VERSION 5.7 ;
  NOWIREEXTENSIONATPIN ON ;
  DIVIDERCHAR "/" ;
  BUSBITCHARS "[]" ;
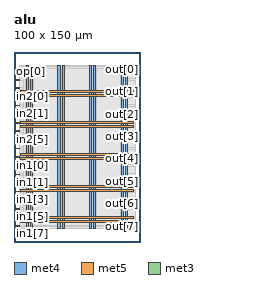
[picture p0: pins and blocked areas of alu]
MACRO alu
  CLASS BLOCK ;
  FOREIGN alu ;
  ORIGIN 0.000 0.000 ;
  SIZE 100.000 BY 150.000 ;
  PIN VGND
    DIRECTION INOUT ;
    USE GROUND ;
    PORT
      LAYER met4 ;
        RECT 13.020 10.640 14.620 138.960 ;
    END
    PORT
      LAYER met4 ;
        RECT 38.020 10.640 39.620 138.960 ;
    END
    PORT
      LAYER met4 ;
        RECT 63.020 10.640 64.620 138.960 ;
    END
    PORT
      LAYER met4 ;
        RECT 88.020 10.640 89.620 138.960 ;
    END
    PORT
      LAYER met5 ;
        RECT 5.280 18.380 94.540 19.980 ;
    END
    PORT
      LAYER met5 ;
        RECT 5.280 43.380 94.540 44.980 ;
    END
    PORT
      LAYER met5 ;
        RECT 5.280 68.380 94.540 69.980 ;
    END
    PORT
      LAYER met5 ;
        RECT 5.280 93.380 94.540 94.980 ;
    END
    PORT
      LAYER met5 ;
        RECT 5.280 118.380 94.540 119.980 ;
    END
  END VGND
  PIN VPWR
    DIRECTION INOUT ;
    USE POWER ;
    PORT
      LAYER met4 ;
        RECT 9.720 10.640 11.320 138.960 ;
    END
    PORT
      LAYER met4 ;
        RECT 34.720 10.640 36.320 138.960 ;
    END
    PORT
      LAYER met4 ;
        RECT 59.720 10.640 61.320 138.960 ;
    END
    PORT
      LAYER met4 ;
        RECT 84.720 10.640 86.320 138.960 ;
    END
    PORT
      LAYER met5 ;
        RECT 5.280 15.080 94.540 16.680 ;
    END
    PORT
      LAYER met5 ;
        RECT 5.280 40.080 94.540 41.680 ;
    END
    PORT
      LAYER met5 ;
        RECT 5.280 65.080 94.540 66.680 ;
    END
    PORT
      LAYER met5 ;
        RECT 5.280 90.080 94.540 91.680 ;
    END
    PORT
      LAYER met5 ;
        RECT 5.280 115.080 94.540 116.680 ;
    END
  END VPWR
  PIN in1[0]
    DIRECTION INPUT ;
    USE SIGNAL ;
    ANTENNAGATEAREA 0.126000 ;
    PORT
      LAYER met3 ;
        RECT 0.000 59.880 4.000 60.480 ;
    END
  END in1[0]
  PIN in1[1]
    DIRECTION INPUT ;
    USE SIGNAL ;
    ANTENNAGATEAREA 0.213000 ;
    PORT
      LAYER met3 ;
        RECT 0.000 53.080 4.000 53.680 ;
    END
  END in1[1]
  PIN in1[2]
    DIRECTION INPUT ;
    USE SIGNAL ;
    ANTENNAGATEAREA 0.159000 ;
    PORT
      LAYER met3 ;
        RECT 0.000 46.280 4.000 46.880 ;
    END
  END in1[2]
  PIN in1[3]
    DIRECTION INPUT ;
    USE SIGNAL ;
    ANTENNAGATEAREA 0.159000 ;
    PORT
      LAYER met3 ;
        RECT 0.000 39.480 4.000 40.080 ;
    END
  END in1[3]
  PIN in1[4]
    DIRECTION INPUT ;
    USE SIGNAL ;
    ANTENNAGATEAREA 0.159000 ;
    PORT
      LAYER met3 ;
        RECT 0.000 32.680 4.000 33.280 ;
    END
  END in1[4]
  PIN in1[5]
    DIRECTION INPUT ;
    USE SIGNAL ;
    ANTENNAGATEAREA 0.159000 ;
    PORT
      LAYER met3 ;
        RECT 0.000 25.880 4.000 26.480 ;
    END
  END in1[5]
  PIN in1[6]
    DIRECTION INPUT ;
    USE SIGNAL ;
    ANTENNAGATEAREA 0.159000 ;
    PORT
      LAYER met3 ;
        RECT 0.000 19.080 4.000 19.680 ;
    END
  END in1[6]
  PIN in1[7]
    DIRECTION INPUT ;
    USE SIGNAL ;
    ANTENNAGATEAREA 0.247500 ;
    PORT
      LAYER met3 ;
        RECT 0.000 12.280 4.000 12.880 ;
    END
  END in1[7]
  PIN in2[0]
    DIRECTION INPUT ;
    USE SIGNAL ;
    ANTENNAGATEAREA 0.213000 ;
    PORT
      LAYER met3 ;
        RECT 0.000 114.280 4.000 114.880 ;
    END
  END in2[0]
  PIN in2[1]
    DIRECTION INPUT ;
    USE SIGNAL ;
    ANTENNAGATEAREA 0.159000 ;
    PORT
      LAYER met3 ;
        RECT 0.000 107.480 4.000 108.080 ;
    END
  END in2[1]
  PIN in2[2]
    DIRECTION INPUT ;
    USE SIGNAL ;
    ANTENNAGATEAREA 0.213000 ;
    PORT
      LAYER met3 ;
        RECT 0.000 100.680 4.000 101.280 ;
    END
  END in2[2]
  PIN in2[3]
    DIRECTION INPUT ;
    USE SIGNAL ;
    ANTENNAGATEAREA 0.213000 ;
    PORT
      LAYER met3 ;
        RECT 0.000 93.880 4.000 94.480 ;
    END
  END in2[3]
  PIN in2[4]
    DIRECTION INPUT ;
    USE SIGNAL ;
    ANTENNAGATEAREA 0.213000 ;
    PORT
      LAYER met3 ;
        RECT 0.000 87.080 4.000 87.680 ;
    END
  END in2[4]
  PIN in2[5]
    DIRECTION INPUT ;
    USE SIGNAL ;
    ANTENNAGATEAREA 0.159000 ;
    PORT
      LAYER met3 ;
        RECT 0.000 80.280 4.000 80.880 ;
    END
  END in2[5]
  PIN in2[6]
    DIRECTION INPUT ;
    USE SIGNAL ;
    ANTENNAGATEAREA 0.159000 ;
    PORT
      LAYER met3 ;
        RECT 0.000 73.480 4.000 74.080 ;
    END
  END in2[6]
  PIN in2[7]
    DIRECTION INPUT ;
    USE SIGNAL ;
    ANTENNAGATEAREA 0.213000 ;
    PORT
      LAYER met3 ;
        RECT 0.000 66.680 4.000 67.280 ;
    END
  END in2[7]
  PIN op[0]
    DIRECTION INPUT ;
    USE SIGNAL ;
    ANTENNAGATEAREA 0.159000 ;
    PORT
      LAYER met3 ;
        RECT 0.000 134.680 4.000 135.280 ;
    END
  END op[0]
  PIN op[1]
    DIRECTION INPUT ;
    USE SIGNAL ;
    ANTENNAGATEAREA 0.213000 ;
    PORT
      LAYER met3 ;
        RECT 0.000 127.880 4.000 128.480 ;
    END
  END op[1]
  PIN op[2]
    DIRECTION INPUT ;
    USE SIGNAL ;
    ANTENNAGATEAREA 0.213000 ;
    PORT
      LAYER met3 ;
        RECT 0.000 121.080 4.000 121.680 ;
    END
  END op[2]
  PIN out[0]
    DIRECTION OUTPUT ;
    USE SIGNAL ;
    ANTENNADIFFAREA 0.445500 ;
    PORT
      LAYER met3 ;
        RECT 96.000 136.040 100.000 136.640 ;
    END
  END out[0]
  PIN out[1]
    DIRECTION OUTPUT ;
    USE SIGNAL ;
    ANTENNADIFFAREA 0.445500 ;
    PORT
      LAYER met3 ;
        RECT 96.000 118.360 100.000 118.960 ;
    END
  END out[1]
  PIN out[2]
    DIRECTION OUTPUT ;
    USE SIGNAL ;
    ANTENNADIFFAREA 0.445500 ;
    PORT
      LAYER met3 ;
        RECT 96.000 100.680 100.000 101.280 ;
    END
  END out[2]
  PIN out[3]
    DIRECTION OUTPUT ;
    USE SIGNAL ;
    ANTENNADIFFAREA 0.445500 ;
    PORT
      LAYER met3 ;
        RECT 96.000 83.000 100.000 83.600 ;
    END
  END out[3]
  PIN out[4]
    DIRECTION OUTPUT ;
    USE SIGNAL ;
    ANTENNADIFFAREA 0.445500 ;
    PORT
      LAYER met3 ;
        RECT 96.000 65.320 100.000 65.920 ;
    END
  END out[4]
  PIN out[5]
    DIRECTION OUTPUT ;
    USE SIGNAL ;
    ANTENNADIFFAREA 0.445500 ;
    PORT
      LAYER met3 ;
        RECT 96.000 47.640 100.000 48.240 ;
    END
  END out[5]
  PIN out[6]
    DIRECTION OUTPUT ;
    USE SIGNAL ;
    ANTENNADIFFAREA 0.445500 ;
    PORT
      LAYER met3 ;
        RECT 96.000 29.960 100.000 30.560 ;
    END
  END out[6]
  PIN out[7]
    DIRECTION OUTPUT ;
    USE SIGNAL ;
    ANTENNADIFFAREA 1.336500 ;
    PORT
      LAYER met3 ;
        RECT 96.000 12.280 100.000 12.880 ;
    END
  END out[7]
  OBS
      LAYER nwell ;
        RECT 5.330 10.795 94.490 138.910 ;
      LAYER li1 ;
        RECT 5.520 10.795 94.300 138.805 ;
      LAYER met1 ;
        RECT 4.210 10.640 95.610 138.960 ;
      LAYER met2 ;
        RECT 4.230 10.695 95.580 138.905 ;
      LAYER met3 ;
        RECT 3.990 137.040 96.000 138.885 ;
        RECT 3.990 135.680 95.600 137.040 ;
        RECT 4.400 135.640 95.600 135.680 ;
        RECT 4.400 134.280 96.000 135.640 ;
        RECT 3.990 128.880 96.000 134.280 ;
        RECT 4.400 127.480 96.000 128.880 ;
        RECT 3.990 122.080 96.000 127.480 ;
        RECT 4.400 120.680 96.000 122.080 ;
        RECT 3.990 119.360 96.000 120.680 ;
        RECT 3.990 117.960 95.600 119.360 ;
        RECT 3.990 115.280 96.000 117.960 ;
        RECT 4.400 113.880 96.000 115.280 ;
        RECT 3.990 108.480 96.000 113.880 ;
        RECT 4.400 107.080 96.000 108.480 ;
        RECT 3.990 101.680 96.000 107.080 ;
        RECT 4.400 100.280 95.600 101.680 ;
        RECT 3.990 94.880 96.000 100.280 ;
        RECT 4.400 93.480 96.000 94.880 ;
        RECT 3.990 88.080 96.000 93.480 ;
        RECT 4.400 86.680 96.000 88.080 ;
        RECT 3.990 84.000 96.000 86.680 ;
        RECT 3.990 82.600 95.600 84.000 ;
        RECT 3.990 81.280 96.000 82.600 ;
        RECT 4.400 79.880 96.000 81.280 ;
        RECT 3.990 74.480 96.000 79.880 ;
        RECT 4.400 73.080 96.000 74.480 ;
        RECT 3.990 67.680 96.000 73.080 ;
        RECT 4.400 66.320 96.000 67.680 ;
        RECT 4.400 66.280 95.600 66.320 ;
        RECT 3.990 64.920 95.600 66.280 ;
        RECT 3.990 60.880 96.000 64.920 ;
        RECT 4.400 59.480 96.000 60.880 ;
        RECT 3.990 54.080 96.000 59.480 ;
        RECT 4.400 52.680 96.000 54.080 ;
        RECT 3.990 48.640 96.000 52.680 ;
        RECT 3.990 47.280 95.600 48.640 ;
        RECT 4.400 47.240 95.600 47.280 ;
        RECT 4.400 45.880 96.000 47.240 ;
        RECT 3.990 40.480 96.000 45.880 ;
        RECT 4.400 39.080 96.000 40.480 ;
        RECT 3.990 33.680 96.000 39.080 ;
        RECT 4.400 32.280 96.000 33.680 ;
        RECT 3.990 30.960 96.000 32.280 ;
        RECT 3.990 29.560 95.600 30.960 ;
        RECT 3.990 26.880 96.000 29.560 ;
        RECT 4.400 25.480 96.000 26.880 ;
        RECT 3.990 20.080 96.000 25.480 ;
        RECT 4.400 18.680 96.000 20.080 ;
        RECT 3.990 13.280 96.000 18.680 ;
        RECT 4.400 11.880 95.600 13.280 ;
        RECT 3.990 10.715 96.000 11.880 ;
      LAYER met4 ;
        RECT 7.655 19.895 9.320 137.185 ;
        RECT 11.720 19.895 12.620 137.185 ;
        RECT 15.020 19.895 34.320 137.185 ;
        RECT 36.720 19.895 37.620 137.185 ;
        RECT 40.020 19.895 59.320 137.185 ;
        RECT 61.720 19.895 62.620 137.185 ;
        RECT 65.020 19.895 84.320 137.185 ;
  END
END alu
END LIBRARY

